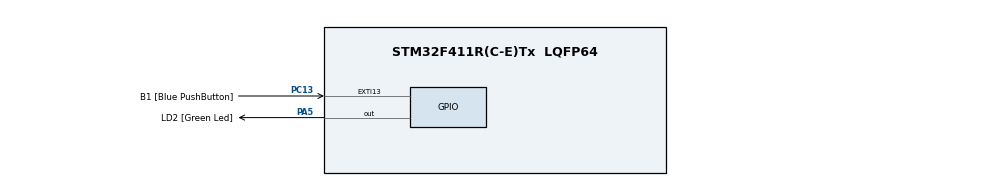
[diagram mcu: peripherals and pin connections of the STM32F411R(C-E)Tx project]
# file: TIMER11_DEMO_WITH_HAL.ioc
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Mcu.Family=STM32F4
Mcu.Name=STM32F411R(C-E)Tx
Mcu.Package=LQFP64
NVIC.PriorityGroup=NVIC_PRIORITYGROUP_0
NVIC.TIM1_TRG_COM_TIM11_IRQn=true\:0\:0\:false\:false\:true\:true\:true\:true
PA13.GPIO_Label=TMS
PA13.Signal=SYS_JTMS-SWDIO
PA14.GPIO_Label=TCK
PA14.Signal=SYS_JTCK-SWCLK
PA5.GPIO_Label=LD2 [Green Led]
PA5.Signal=GPIO_Output
PB3.GPIO_Label=SWO
PB3.Signal=SYS_JTDO-SWO
PC13-ANTI_TAMP.GPIO_Label=B1 [Blue PushButton]
PC13-ANTI_TAMP.GPIO_ModeDefaultEXTI=GPIO_MODE_IT_FALLING
PC13-ANTI_TAMP.Signal=GPXTI13
PC14-OSC32_IN.Signal=RCC_OSC32_IN
PC15-OSC32_OUT.Signal=RCC_OSC32_OUT
PH0\ -\ OSC_IN.Signal=RCC_OSC_IN
PH1\ -\ OSC_OUT.Signal=RCC_OSC_OUT
ProjectManager.HeapSize=0x200
ProjectManager.StackSize=0x400
ProjectManager.TargetToolchain=STM32CubeIDE
RCC.48MHZClocksFreq_Value=84000000
RCC.AHBFreq_Value=84000000
RCC.APB1CLKDivider=RCC_HCLK_DIV2
RCC.APB1Freq_Value=42000000
RCC.APB1TimFreq_Value=84000000
RCC.APB2Freq_Value=84000000
RCC.APB2TimFreq_Value=84000000
RCC.CortexFreq_Value=84000000
RCC.FLatency-AdvancedSettings=FLASH_LATENCY_2
RCC.HCLKFreq_Value=84000000
RCC.HSE_VALUE=8000000
RCC.HSI_VALUE=16000000
RCC.LSE_VALUE=32768
RCC.PLLN=336
RCC.PLLP=RCC_PLLP_DIV4
RCC.SYSCLKFreq_VALUE=84000000
RCC.SYSCLKSource=RCC_SYSCLKSOURCE_PLLCLK
RCC.VCOOutputFreq_Value=336000000
TIM11.Period=1000
TIM11.Prescaler=15999
VP_TIM11_VS_ClockSourceINT.Mode=Enable_Timer
board=NUCLEO-F411RE

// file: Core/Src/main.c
/* USER CODE BEGIN Header */
/**
  ******************************************************************************
  * @file           : main.c
  * @brief          : Main program body
  ******************************************************************************
  * @attention
  *
  * Copyright (c) 2022 STMicroelectronics.
  * All rights reserved.
  *
  * This software is licensed under terms that can be found in the LICENSE file
  * in the root directory of this software component.
  * If no LICENSE file comes with this software, it is provided AS-IS.
  *
  ******************************************************************************
  */
/* USER CODE END Header */
#include "main.h"

TIM_HandleTypeDef htim11;

void SystemClock_Config(void);
static void MX_GPIO_Init(void);
static void MX_TIM11_Init(void);

int main(void)
{

  /* MCU Configuration--------------------------------------------------------*/

  /* Reset of all peripherals, Initializes the Flash interface and the Systick. */
  HAL_Init();

  /* Configure the system clock */
  SystemClock_Config();

  /* Initialize all configured peripherals */
  MX_GPIO_Init();
  MX_TIM11_Init();
  /* USER CODE BEGIN 2 */
  HAL_TIM_Base_Start_IT(&htim11);
  /* USER CODE END 2 */

  /* Infinite loop */
  while (1)
  {

  }
}

void SystemClock_Config(void)
{
  RCC_OscInitTypeDef RCC_OscInitStruct = {0};
  RCC_ClkInitTypeDef RCC_ClkInitStruct = {0};

  /** Configure the main internal regulator output voltage
  */
  __HAL_RCC_PWR_CLK_ENABLE();
  __HAL_PWR_VOLTAGESCALING_CONFIG(PWR_REGULATOR_VOLTAGE_SCALE1);

  /** Initializes the RCC Oscillators according to the specified parameters
  * in the RCC_OscInitTypeDef structure.
  */
  RCC_OscInitStruct.OscillatorType = RCC_OSCILLATORTYPE_HSI;
  RCC_OscInitStruct.HSIState = RCC_HSI_ON;
  RCC_OscInitStruct.HSICalibrationValue = RCC_HSICALIBRATION_DEFAULT;
  RCC_OscInitStruct.PLL.PLLState = RCC_PLL_NONE;
  if (HAL_RCC_OscConfig(&RCC_OscInitStruct) != HAL_OK)
  {
    Error_Handler();
  }

  /** Initializes the CPU, AHB and APB buses clocks
  */
  RCC_ClkInitStruct.ClockType = RCC_CLOCKTYPE_HCLK|RCC_CLOCKTYPE_SYSCLK
                              |RCC_CLOCKTYPE_PCLK1|RCC_CLOCKTYPE_PCLK2;
  RCC_ClkInitStruct.SYSCLKSource = RCC_SYSCLKSOURCE_HSI;
  RCC_ClkInitStruct.AHBCLKDivider = RCC_SYSCLK_DIV1;
  RCC_ClkInitStruct.APB1CLKDivider = RCC_HCLK_DIV2;
  RCC_ClkInitStruct.APB2CLKDivider = RCC_HCLK_DIV1;

  if (HAL_RCC_ClockConfig(&RCC_ClkInitStruct, FLASH_LATENCY_0) != HAL_OK)
  {
    Error_Handler();
  }
}

static void MX_TIM11_Init(void)
{

  htim11.Instance = TIM11;
  htim11.Init.Prescaler = 15999;
  htim11.Init.CounterMode = TIM_COUNTERMODE_UP;
  htim11.Init.Period = 1000;
  htim11.Init.ClockDivision = TIM_CLOCKDIVISION_DIV1;
  htim11.Init.AutoReloadPreload = TIM_AUTORELOAD_PRELOAD_DISABLE;
  if (HAL_TIM_Base_Init(&htim11) != HAL_OK)
  {
    Error_Handler();
  }

}

static void MX_GPIO_Init(void)
{
  GPIO_InitTypeDef GPIO_InitStruct = {0};

  /* GPIO Ports Clock Enable */
  __HAL_RCC_GPIOC_CLK_ENABLE();
  __HAL_RCC_GPIOH_CLK_ENABLE();
  __HAL_RCC_GPIOA_CLK_ENABLE();
  __HAL_RCC_GPIOB_CLK_ENABLE();

  /*Configure GPIO pin Output Level */
  HAL_GPIO_WritePin(LD2_GPIO_Port, LD2_Pin, GPIO_PIN_RESET);

  /*Configure GPIO pin : B1_Pin */
  GPIO_InitStruct.Pin = B1_Pin;
  GPIO_InitStruct.Mode = GPIO_MODE_IT_FALLING;
  GPIO_InitStruct.Pull = GPIO_NOPULL;
  HAL_GPIO_Init(B1_GPIO_Port, &GPIO_InitStruct);

  /*Configure GPIO pin : LD2_Pin */
  GPIO_InitStruct.Pin = LD2_Pin;
  GPIO_InitStruct.Mode = GPIO_MODE_OUTPUT_PP;
  GPIO_InitStruct.Pull = GPIO_NOPULL;
  GPIO_InitStruct.Speed = GPIO_SPEED_FREQ_LOW;
  HAL_GPIO_Init(LD2_GPIO_Port, &GPIO_InitStruct);

}

void Error_Handler(void)
{
  __disable_irq();
  while (1)
  {
  }
}
